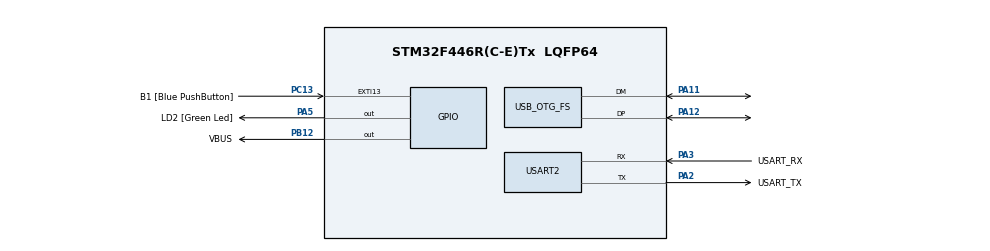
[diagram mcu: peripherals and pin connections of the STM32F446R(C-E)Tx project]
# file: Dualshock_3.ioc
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FREERTOS.Mutexes01=usbhMutex,Dynamic,NULL;uart2Mutex,Dynamic,NULL
FREERTOS.Queues01=reportQueue,2,DS3_report,0,Dynamic,NULL,NULL
FREERTOS.Tasks01=defaultTask,24,128,StartDefaultTask,Default,NULL,Dynamic,NULL,NULL;usbhTask,24,128,usbhTaskFunction,Default,NULL,Dynamic,NULL,NULL;processReport,24,1024,processReportFunction,Default,NULL,Dynamic,NULL,NULL
Mcu.Family=STM32F4
Mcu.Name=STM32F446R(C-E)Tx
Mcu.Package=LQFP64
NVIC.OTG_FS_IRQn=true\:5\:0\:false\:false\:true\:true\:false\:true
NVIC.PriorityGroup=NVIC_PRIORITYGROUP_4
NVIC.TIM6_DAC_IRQn=true\:0\:0\:false\:false\:true\:false\:false\:true
NVIC.TimeBase=TIM6_DAC_IRQn
NVIC.TimeBaseIP=TIM6
PA11.Mode=Host_Only
PA11.Signal=USB_OTG_FS_DM
PA12.Mode=Host_Only
PA12.Signal=USB_OTG_FS_DP
PA13.GPIO_Label=TMS
PA13.Mode=Serial_Wire
PA13.Signal=SYS_JTMS-SWDIO
PA14.GPIO_Label=TCK
PA14.Mode=Serial_Wire
PA14.Signal=SYS_JTCK-SWCLK
PA2.GPIO_Label=USART_TX
PA2.Mode=Asynchronous
PA2.Signal=USART2_TX
PA3.GPIO_Label=USART_RX
PA3.Mode=Asynchronous
PA3.Signal=USART2_RX
PA5.GPIO_Label=LD2 [Green Led]
PA5.Signal=GPIO_Output
PB12.GPIO_Label=VBUS
PB12.Signal=GPIO_Output
PB3.GPIO_Label=SWO
PB3.Signal=SYS_JTDO-SWO
PC13.GPIO_Label=B1 [Blue PushButton]
PC13.GPIO_ModeDefaultEXTI=GPIO_MODE_IT_FALLING
PC13.Signal=GPXTI13
PC14-OSC32_IN.Mode=LSE-External-Oscillator
PC14-OSC32_IN.Signal=RCC_OSC32_IN
PC15-OSC32_OUT.Mode=LSE-External-Oscillator
PC15-OSC32_OUT.Signal=RCC_OSC32_OUT
PH0-OSC_IN.Mode=HSE-External-Oscillator
PH0-OSC_IN.Signal=RCC_OSC_IN
PH1-OSC_OUT.Mode=HSE-External-Oscillator
PH1-OSC_OUT.Signal=RCC_OSC_OUT
ProjectManager.HeapSize=0x200
ProjectManager.StackSize=0x400
ProjectManager.TargetToolchain=STM32CubeIDE
RCC.48MHZClocksFreq_Value=84000000
RCC.AHBFreq_Value=72000000
RCC.APB1CLKDivider=RCC_HCLK_DIV2
RCC.APB1Freq_Value=36000000
RCC.APB1TimFreq_Value=72000000
RCC.APB2Freq_Value=72000000
RCC.APB2TimFreq_Value=72000000
RCC.CortexFreq_Value=72000000
RCC.FLatency-AdvancedSettings=FLASH_LATENCY_2
RCC.HCLKFreq_Value=72000000
RCC.HSE_VALUE=8000000
RCC.HSI_VALUE=16000000
RCC.PLLM=4
RCC.PLLN=72
RCC.PLLQ=3
RCC.SYSCLKFreq_VALUE=72000000
RCC.SYSCLKSource=RCC_SYSCLKSOURCE_PLLCLK
RCC.USBFreq_Value=48000000
RCC.VCOOutputFreq_Value=144000000
USART2.VirtualMode=VM_ASYNC
USB_HOST.BSP.number=1
USB_HOST.USBH_HandleTypeDef-MSC_FS=hUsbHostFS
USB_HOST.VirtualModeFS=Msc
USB_HOST0.BSP.STBoard=false
USB_HOST0.BSP.api=Unknown
USB_HOST0.BSP.i2caddr=0
USB_HOST0.BSP.instance=PB12
USB_HOST0.BSP.ip=GPIO
USB_HOST0.BSP.mode=Output
USB_HOST0.BSP.name=Drive_VBUS_FS
USB_HOST0.BSP.solution=PB12
USB_OTG_FS.VirtualMode=Host_Only
USB_OTG_FS.phy_itface=HCD_PHY_EMBEDDED
VP_FREERTOS_VS_CMSIS_V2.Mode=CMSIS_V2
VP_SYS_VS_tim6.Mode=TIM6
VP_USB_HOST_VS_USB_HOST_MSC_FS.Mode=MSC_FS
board=NUCLEO-F446RE

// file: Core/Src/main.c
/* USER CODE BEGIN Header */
/**
 ******************************************************************************
 * @file           : main.c
 * @brief          : Main program body
 ******************************************************************************
 * @attention
 *
 * <h2><center>&copy; Copyright (c) 2020 STMicroelectronics.
 * All rights reserved.</center></h2>
 *
 * This software component is licensed by ST under Ultimate Liberty license
 * SLA0044, the "License"; You may not use this file except in compliance with
 * the License. You may obtain a copy of the License at:
 *                             www.st.com/SLA0044
 *
 ******************************************************************************
 */

/* USER CODE END Header */
#include "main.h"
#include "cmsis_os.h"
#include "usb_host.h"

/* USER CODE BEGIN Includes */

#include "USBH_HID_generic/usbh_hid.h"
#include "stdio.h"
#include "Dualshock3_driver.h"

/* USER CODE END Includes */

UART_HandleTypeDef huart2;

/* Definitions for defaultTask */
osThreadId_t defaultTaskHandle;
const osThreadAttr_t defaultTask_attributes = {
  .name = "defaultTask",
  .priority = (osPriority_t) osPriorityNormal,
  .stack_size = 128 * 4
};
/* Definitions for usbhTask */
osThreadId_t usbhTaskHandle;
const osThreadAttr_t usbhTask_attributes = {
  .name = "usbhTask",
  .priority = (osPriority_t) osPriorityNormal,
  .stack_size = 128 * 4
};
/* Definitions for processReport */
osThreadId_t processReportHandle;
const osThreadAttr_t processReport_attributes = {
  .name = "processReport",
  .priority = (osPriority_t) osPriorityNormal,
  .stack_size = 1024 * 4
};
/* Definitions for reportQueue */
osMessageQueueId_t reportQueueHandle;
const osMessageQueueAttr_t reportQueue_attributes = {
  .name = "reportQueue"
};
/* Definitions for usbhMutex */
osMutexId_t usbhMutexHandle;
const osMutexAttr_t usbhMutex_attributes = {
  .name = "usbhMutex"
};
/* Definitions for uart2Mutex */
osMutexId_t uart2MutexHandle;
const osMutexAttr_t uart2Mutex_attributes = {
  .name = "uart2Mutex"
};

void SystemClock_Config(void);
static void MX_GPIO_Init(void);
static void MX_USART2_UART_Init(void);
void StartDefaultTask(void *argument);
void usbhTaskFunction(void *argument);
void processReportFunction(void *argument);

/* USER CODE BEGIN 0 */

void Dualshock3_newReport_CB(DS3_report* report)
{
	if(osMessageQueueGetSpace(reportQueueHandle) == 0)
	{
		osMessageQueueReset(reportQueueHandle);
	}
	osMessageQueuePut(reportQueueHandle, report, 0, 0);
}

void Dualshock3_connected_CB()
{
	// use semaphore to start report task
}

/* USER CODE END 0 */

int main(void)
{

  /* MCU Configuration--------------------------------------------------------*/

  /* Reset of all peripherals, Initializes the Flash interface and the Systick. */
  HAL_Init();

  /* Configure the system clock */
  SystemClock_Config();

  /* Initialize all configured peripherals */
  MX_GPIO_Init();
  MX_USART2_UART_Init();
  /* USER CODE BEGIN 2 */

	MX_USB_HOST_Init();

	// stops the broken auto generated thread for the usbh process
	MX_USB_HOST_SuspendThread();

	// loads the dualshock 3 driver
	USBH_HID_GenericRegisterDriver(dualshock3_Driver);

  /* USER CODE END 2 */

  /* Init scheduler */
  osKernelInitialize();
  /* Create the mutex(es) */
  /* creation of usbhMutex */
  usbhMutexHandle = osMutexNew(&usbhMutex_attributes);

  /* creation of uart2Mutex */
  uart2MutexHandle = osMutexNew(&uart2Mutex_attributes);

  /* Create the queue(s) */
  /* creation of reportQueue */
  reportQueueHandle = osMessageQueueNew (2, sizeof(DS3_report), &reportQueue_attributes);

  /* Create the thread(s) */
  /* creation of defaultTask */
  defaultTaskHandle = osThreadNew(StartDefaultTask, NULL, &defaultTask_attributes);

  /* creation of usbhTask */
  usbhTaskHandle = osThreadNew(usbhTaskFunction, NULL, &usbhTask_attributes);

  /* creation of processReport */
  processReportHandle = osThreadNew(processReportFunction, NULL, &processReport_attributes);

  /* Start scheduler */
  osKernelStart();

  /* We should never get here as control is now taken by the scheduler */
  /* Infinite loop */
	while (1)
	{

	}
}

void SystemClock_Config(void)
{
  RCC_OscInitTypeDef RCC_OscInitStruct = {0};
  RCC_ClkInitTypeDef RCC_ClkInitStruct = {0};
  RCC_PeriphCLKInitTypeDef PeriphClkInitStruct = {0};

  /** Configure the main internal regulator output voltage
  */
  __HAL_RCC_PWR_CLK_ENABLE();
  __HAL_PWR_VOLTAGESCALING_CONFIG(PWR_REGULATOR_VOLTAGE_SCALE1);
  /** Initializes the RCC Oscillators according to the specified parameters
  * in the RCC_OscInitTypeDef structure.
  */
  RCC_OscInitStruct.OscillatorType = RCC_OSCILLATORTYPE_HSE;
  RCC_OscInitStruct.HSEState = RCC_HSE_ON;
  RCC_OscInitStruct.PLL.PLLState = RCC_PLL_ON;
  RCC_OscInitStruct.PLL.PLLSource = RCC_PLLSOURCE_HSE;
  RCC_OscInitStruct.PLL.PLLM = 8;
  RCC_OscInitStruct.PLL.PLLN = 336;
  RCC_OscInitStruct.PLL.PLLP = RCC_PLLP_DIV2;
  RCC_OscInitStruct.PLL.PLLQ = 7;
  RCC_OscInitStruct.PLL.PLLR = 2;
  if (HAL_RCC_OscConfig(&RCC_OscInitStruct) != HAL_OK)
  {
    Error_Handler();
  }
  /** Initializes the CPU, AHB and APB buses clocks
  */
  RCC_ClkInitStruct.ClockType = RCC_CLOCKTYPE_HCLK|RCC_CLOCKTYPE_SYSCLK
                              |RCC_CLOCKTYPE_PCLK1|RCC_CLOCKTYPE_PCLK2;
  RCC_ClkInitStruct.SYSCLKSource = RCC_SYSCLKSOURCE_PLLCLK;
  RCC_ClkInitStruct.AHBCLKDivider = RCC_SYSCLK_DIV1;
  RCC_ClkInitStruct.APB1CLKDivider = RCC_HCLK_DIV4;
  RCC_ClkInitStruct.APB2CLKDivider = RCC_HCLK_DIV2;

  if (HAL_RCC_ClockConfig(&RCC_ClkInitStruct, FLASH_LATENCY_5) != HAL_OK)
  {
    Error_Handler();
  }
  PeriphClkInitStruct.PeriphClockSelection = RCC_PERIPHCLK_CLK48;
  PeriphClkInitStruct.Clk48ClockSelection = RCC_CLK48CLKSOURCE_PLLQ;
  if (HAL_RCCEx_PeriphCLKConfig(&PeriphClkInitStruct) != HAL_OK)
  {
    Error_Handler();
  }
}

static void MX_USART2_UART_Init(void)
{

  huart2.Instance = USART2;
  huart2.Init.BaudRate = 115200;
  huart2.Init.WordLength = UART_WORDLENGTH_8B;
  huart2.Init.StopBits = UART_STOPBITS_1;
  huart2.Init.Parity = UART_PARITY_NONE;
  huart2.Init.Mode = UART_MODE_TX_RX;
  huart2.Init.HwFlowCtl = UART_HWCONTROL_NONE;
  huart2.Init.OverSampling = UART_OVERSAMPLING_16;
  if (HAL_UART_Init(&huart2) != HAL_OK)
  {
    Error_Handler();
  }

}

static void MX_GPIO_Init(void)
{

  /* GPIO Ports Clock Enable */
  __HAL_RCC_GPIOH_CLK_ENABLE();
  __HAL_RCC_GPIOA_CLK_ENABLE();

}

void StartDefaultTask(void *argument)
{
  /* init code for USB_HOST */
  MX_USB_HOST_Init();
  for(;;)
  {
    osDelay(1);
  }
}

void usbhTaskFunction(void *argument)
{
  for(;;)
  {
    osDelay(1);
  }
}

void processReportFunction(void *argument)
{
  for(;;)
  {
    osDelay(1);
  }
}

 /**
  * @brief  Period elapsed callback in non blocking mode
  * @note   This function is called  when TIM6 interrupt took place, inside
  * HAL_TIM_IRQHandler(). It makes a direct call to HAL_IncTick() to increment
  * a global variable "uwTick" used as application time base.
  * @param  htim : TIM handle
  * @retval None
  */
void HAL_TIM_PeriodElapsedCallback(TIM_HandleTypeDef *htim)
{
  if (htim->Instance == TIM6) {
    HAL_IncTick();
  }
}

void Error_Handler(void)
{
}

/************************ (C) COPYRIGHT STMicroelectronics *****END OF FILE****/
